VERSION 5.7 ;
  NOWIREEXTENSIONATPIN ON ;
  DIVIDERCHAR "/" ;
  BUSBITCHARS "[]" ;
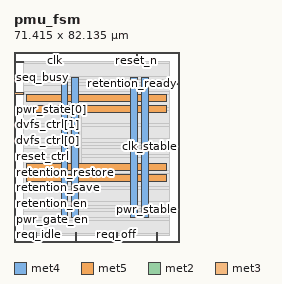
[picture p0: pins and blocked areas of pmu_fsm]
MACRO pmu_fsm
  CLASS BLOCK ;
  FOREIGN pmu_fsm ;
  ORIGIN 0.000 0.000 ;
  SIZE 71.415 BY 82.135 ;
  PIN VGND
    DIRECTION INOUT ;
    USE GROUND ;
    PORT
      LAYER met4 ;
        RECT 25.040 10.640 28.040 70.960 ;
    END
    PORT
      LAYER met4 ;
        RECT 55.040 10.640 58.040 70.960 ;
    END
    PORT
      LAYER met5 ;
        RECT 5.280 30.730 66.020 33.730 ;
    END
    PORT
      LAYER met5 ;
        RECT 5.280 60.730 66.020 63.730 ;
    END
  END VGND
  PIN VPWR
    DIRECTION INOUT ;
    USE POWER ;
    PORT
      LAYER met4 ;
        RECT 20.340 10.640 23.340 70.960 ;
    END
    PORT
      LAYER met4 ;
        RECT 50.340 10.640 53.340 70.960 ;
    END
    PORT
      LAYER met5 ;
        RECT 5.280 26.030 66.020 29.030 ;
    END
    PORT
      LAYER met5 ;
        RECT 5.280 56.030 66.020 59.030 ;
    END
  END VPWR
  PIN clk
    DIRECTION INPUT ;
    USE SIGNAL ;
    ANTENNAGATEAREA 0.852000 ;
    PORT
      LAYER met2 ;
        RECT 17.570 78.135 17.850 82.135 ;
    END
  END clk
  PIN clk_gate_en
    DIRECTION OUTPUT ;
    USE SIGNAL ;
    ANTENNADIFFAREA 0.891000 ;
    PORT
      LAYER met3 ;
        RECT 0.000 2.760 4.000 3.360 ;
    END
  END clk_gate_en
  PIN clk_stable
    DIRECTION INPUT ;
    USE SIGNAL ;
    ANTENNAGATEAREA 0.196500 ;
    PORT
      LAYER met3 ;
        RECT 67.415 40.840 71.415 41.440 ;
    END
  END clk_stable
  PIN dvfs_ctrl[0]
    DIRECTION OUTPUT ;
    USE SIGNAL ;
    PORT
      LAYER met3 ;
        RECT 0.000 43.560 4.000 44.160 ;
    END
  END dvfs_ctrl[0]
  PIN dvfs_ctrl[1]
    DIRECTION OUTPUT ;
    USE SIGNAL ;
    ANTENNADIFFAREA 0.383400 ;
    PORT
      LAYER met3 ;
        RECT 0.000 50.360 4.000 50.960 ;
    END
  END dvfs_ctrl[1]
  PIN error
    DIRECTION OUTPUT ;
    USE SIGNAL ;
    ANTENNADIFFAREA 0.383400 ;
    PORT
      LAYER met3 ;
        RECT 0.000 77.560 4.000 78.160 ;
    END
  END error
  PIN pwr_gate_en
    DIRECTION OUTPUT ;
    USE SIGNAL ;
    ANTENNADIFFAREA 0.891000 ;
    PORT
      LAYER met3 ;
        RECT 0.000 9.560 4.000 10.160 ;
    END
  END pwr_gate_en
  PIN pwr_stable
    DIRECTION INPUT ;
    USE SIGNAL ;
    ANTENNAGATEAREA 0.196500 ;
    PORT
      LAYER met3 ;
        RECT 67.415 13.640 71.415 14.240 ;
    END
  END pwr_stable
  PIN pwr_state[0]
    DIRECTION OUTPUT ;
    USE SIGNAL ;
    ANTENNADIFFAREA 0.383400 ;
    PORT
      LAYER met3 ;
        RECT 0.000 57.160 4.000 57.760 ;
    END
  END pwr_state[0]
  PIN pwr_state[1]
    DIRECTION OUTPUT ;
    USE SIGNAL ;
    ANTENNADIFFAREA 0.383400 ;
    PORT
      LAYER met3 ;
        RECT 0.000 63.960 4.000 64.560 ;
    END
  END pwr_state[1]
  PIN req_idle
    DIRECTION INPUT ;
    USE SIGNAL ;
    ANTENNAGATEAREA 0.196500 ;
    PORT
      LAYER met2 ;
        RECT 9.290 0.000 9.570 4.000 ;
    END
  END req_idle
  PIN req_off
    DIRECTION INPUT ;
    USE SIGNAL ;
    ANTENNAGATEAREA 0.196500 ;
    PORT
      LAYER met2 ;
        RECT 44.250 0.000 44.530 4.000 ;
    END
  END req_off
  PIN req_sleep
    DIRECTION INPUT ;
    USE SIGNAL ;
    ANTENNAGATEAREA 0.196500 ;
    PORT
      LAYER met2 ;
        RECT 26.770 0.000 27.050 4.000 ;
    END
  END req_sleep
  PIN reset_ctrl
    DIRECTION OUTPUT ;
    USE SIGNAL ;
    ANTENNADIFFAREA 0.445500 ;
    PORT
      LAYER met3 ;
        RECT 0.000 36.760 4.000 37.360 ;
    END
  END reset_ctrl
  PIN reset_n
    DIRECTION INPUT ;
    USE SIGNAL ;
    ANTENNAGATEAREA 7.056000 ;
    PORT
      LAYER met2 ;
        RECT 52.990 78.135 53.270 82.135 ;
    END
  END reset_n
  PIN retention_en
    DIRECTION OUTPUT ;
    USE SIGNAL ;
    ANTENNADIFFAREA 0.891000 ;
    PORT
      LAYER met3 ;
        RECT 0.000 16.360 4.000 16.960 ;
    END
  END retention_en
  PIN retention_ready
    DIRECTION INPUT ;
    USE SIGNAL ;
    ANTENNAGATEAREA 0.196500 ;
    PORT
      LAYER met3 ;
        RECT 67.415 68.040 71.415 68.640 ;
    END
  END retention_ready
  PIN retention_restore
    DIRECTION OUTPUT ;
    USE SIGNAL ;
    ANTENNADIFFAREA 0.445500 ;
    PORT
      LAYER met3 ;
        RECT 0.000 29.960 4.000 30.560 ;
    END
  END retention_restore
  PIN retention_save
    DIRECTION OUTPUT ;
    USE SIGNAL ;
    ANTENNADIFFAREA 0.445500 ;
    PORT
      LAYER met3 ;
        RECT 0.000 23.160 4.000 23.760 ;
    END
  END retention_save
  PIN seq_busy
    DIRECTION OUTPUT ;
    USE SIGNAL ;
    ANTENNADIFFAREA 0.383400 ;
    PORT
      LAYER met3 ;
        RECT 0.000 70.760 4.000 71.360 ;
    END
  END seq_busy
  PIN wake_up
    DIRECTION INPUT ;
    USE SIGNAL ;
    ANTENNAGATEAREA 0.196500 ;
    PORT
      LAYER met2 ;
        RECT 61.730 0.000 62.010 4.000 ;
    END
  END wake_up
  OBS
      LAYER nwell ;
        RECT 5.330 10.795 65.970 70.805 ;
      LAYER li1 ;
        RECT 5.520 10.795 65.780 70.805 ;
      LAYER met1 ;
        RECT 4.210 10.240 65.780 70.960 ;
      LAYER met2 ;
        RECT 4.230 77.855 17.290 78.135 ;
        RECT 18.130 77.855 52.710 78.135 ;
        RECT 53.550 77.855 64.310 78.135 ;
        RECT 4.230 4.280 64.310 77.855 ;
        RECT 4.230 2.875 9.010 4.280 ;
        RECT 9.850 2.875 26.490 4.280 ;
        RECT 27.330 2.875 43.970 4.280 ;
        RECT 44.810 2.875 61.450 4.280 ;
        RECT 62.290 2.875 64.310 4.280 ;
      LAYER met3 ;
        RECT 4.400 77.160 67.415 78.025 ;
        RECT 3.990 71.760 67.415 77.160 ;
        RECT 4.400 70.360 67.415 71.760 ;
        RECT 3.990 69.040 67.415 70.360 ;
        RECT 3.990 67.640 67.015 69.040 ;
        RECT 3.990 64.960 67.415 67.640 ;
        RECT 4.400 63.560 67.415 64.960 ;
        RECT 3.990 58.160 67.415 63.560 ;
        RECT 4.400 56.760 67.415 58.160 ;
        RECT 3.990 51.360 67.415 56.760 ;
        RECT 4.400 49.960 67.415 51.360 ;
        RECT 3.990 44.560 67.415 49.960 ;
        RECT 4.400 43.160 67.415 44.560 ;
        RECT 3.990 41.840 67.415 43.160 ;
        RECT 3.990 40.440 67.015 41.840 ;
        RECT 3.990 37.760 67.415 40.440 ;
        RECT 4.400 36.360 67.415 37.760 ;
        RECT 3.990 30.960 67.415 36.360 ;
        RECT 4.400 29.560 67.415 30.960 ;
        RECT 3.990 24.160 67.415 29.560 ;
        RECT 4.400 22.760 67.415 24.160 ;
        RECT 3.990 17.360 67.415 22.760 ;
        RECT 4.400 15.960 67.415 17.360 ;
        RECT 3.990 14.640 67.415 15.960 ;
        RECT 3.990 13.240 67.015 14.640 ;
        RECT 3.990 10.560 67.415 13.240 ;
        RECT 4.400 9.160 67.415 10.560 ;
        RECT 3.990 3.760 67.415 9.160 ;
        RECT 4.400 2.895 67.415 3.760 ;
      LAYER met4 ;
        RECT 24.215 30.775 24.640 55.585 ;
        RECT 28.440 30.775 29.145 55.585 ;
  END
END pmu_fsm
END LIBRARY

